VERSION 5.7 ;
  NOWIREEXTENSIONATPIN ON ;
  DIVIDERCHAR "/" ;
  BUSBITCHARS "[]" ;
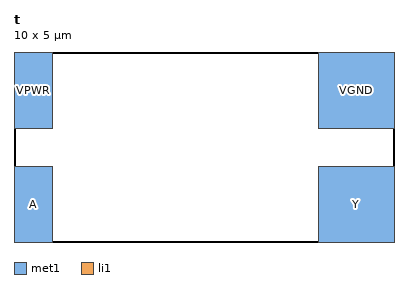
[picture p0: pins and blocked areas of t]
MACRO t
  CLASS BLOCK ;
  FOREIGN t ;
  ORIGIN 0.000 0.000 ;
  SIZE 10.000 BY 5.000 ;
  PIN A
    DIRECTION INPUT ;
    PORT
      LAYER met1 ;
        RECT 0.000 0.000 1.000 2.000 ;
    END
  END A
  PIN Y
    DIRECTION OUTPUT ;
    PORT
      LAYER met1 ;
        RECT 8.000 0.000 10.000 2.000 ;
    END
  END Y
  PIN VGND
    DIRECTION INOUT ;
    USE GROUND ;
    PORT
      LAYER li1 ;
        RECT 8.000 3.000 10.000 5.000 ;
      LAYER met1 ;
        RECT 8.000 3.000 10.000 5.000 ;
    END
  END VGND
  PIN VPWR
    DIRECTION INOUT ;
    USE POWER ;
    PORT
      LAYER li1 ;
        RECT 0.000 3.000 1.000 5.000 ;
      LAYER met1 ;
        RECT 0.000 3.000 1.000 5.000 ;
    END
  END VPWR
END t
END LIBRARY

